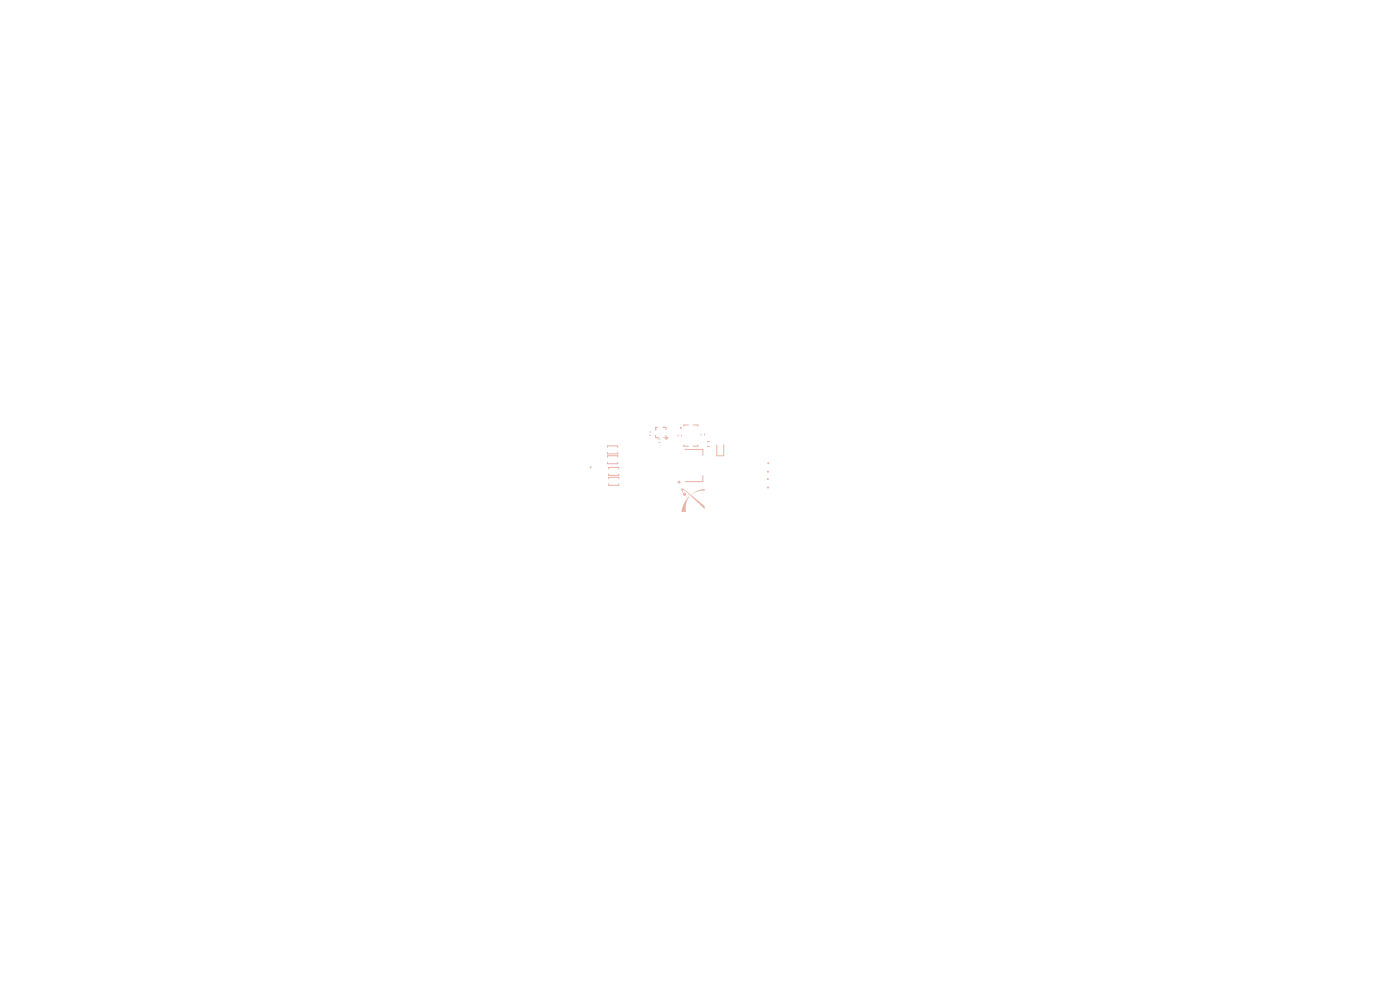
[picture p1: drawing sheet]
<svg xmlns="http://www.w3.org/2000/svg" width="297mm" height="210mm" viewBox="0 0 297 210" stroke-linecap="round" stroke-linejoin="round" font-family="sans-serif">
<g fill="none" stroke="#e8b2a7" stroke-width=".21">
<path d="M129.1 99.5v-.4h2.2v.4M137.8 91.6h.2M137.8 92.4h.2M148.7 92.1v.2M149.5 92.1v.2M150.1 93.7h.4M150.1 94.7h.4M129.1 100.5v.4h2.2v-.4"/>
<circle cx="125.3" cy="99.1" r=".1"/>
<circle cx="162.9" cy="101.6" r=".1"/>
<circle cx="162.9" cy="100.1" r=".1"/>
</g>
<g fill="#e8b2a7">
<path d="M145.5 105.3l.3 .3z"/>
<path d="M146.7 104.8l.1-.1a5.1 5.1 0 0 1 2.7-1v.4l-1.3 .1z"/>
<path d="M146.1 105.3l.2 .1-.1 .1a4 4 0 0 0-.7 3.1h-.9v-.4a5.9 5.9 0 0 1 1.5-2.9z"/>
<path d="M144.5 103.6l.4 .1 .6 .4 3.7 3.1a.56 .56 0 0 1 .3 .8l-4.2-3.9a.24 .24 0 0 0-.4-.1 .24 .24 0 0 0 .1 .4l-.1 .1-.2-.2z"/>
<circle cx="145.2" cy="104.9" r=".33"/>
</g>
<g fill="none" stroke="#e8b2a7" stroke-width=".21">
<path d="M128.9 94.9v-.3h2.2v.3M128.9 96v.3h2.2v-.3M128.9 97v-.3h2.2v.3M128.9 98.1v.3h2.2v-.3M139.1 92.3v.5h.5M139.6 90.6h-.5v.5M139.8 93.1h.2M139.8 93.9h.2M140.8 90.6h.5v.5M140.8 92.8h.3M141.3 92.3v.3M143.8 92.3v.2"/>
<path d="M144.6 92.3v.2M145.1 94.4v.3h1M145.3 95.3h3.8v1.3M146.1 90.1h-1v.3M147.1 90.1h1v.3M148.1 94.4v.3h-1M152.1 94.4v2.3h1.4v-2.3M129.1 101.6v-.4h2.2v.4M129.1 102.6v.4h2.2v-.4M149.1 100.9v1.3h-3.8"/>
<circle cx="144.5" cy="90.8" r=".1"/>
<circle cx="163" cy="98.2" r=".1"/>
<circle cx="162.9" cy="103.4" r=".1"/>
</g>
<g fill="#e8b2a7" stroke="#e8b2a7" stroke-width=".21">
<path d="M144.1 102.1l.2 .3h-.5z"/>
<path d="M141.3 92.8h.4l-.4 .4z"/>
<circle cx="139.1" cy="91.1" r=".06"/>
<circle cx="139.6" cy="92.8" r=".06"/>
<circle cx="140.8" cy="90.6" r=".06"/>
<circle cx="141.3" cy="92.8" r=".06"/>
</g>
</svg>
